VERSION 5.8 ;
BUSBITCHARS "[]" ;
DIVIDERCHAR "/" ;
UNITS
    DATABASE MICRONS 1000 ;
END UNITS

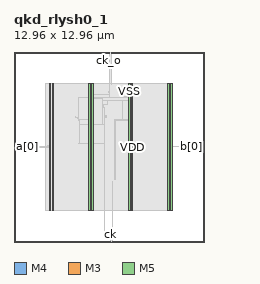
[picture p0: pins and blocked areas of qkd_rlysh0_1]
MACRO qkd_rlysh0_1
  FOREIGN qkd_rlysh0_1 0 0 ;
  CLASS BLOCK ;
  SIZE 12.96 BY 12.96 ;
  PIN a[0]
    DIRECTION INPUT ;
    USE SIGNAL ;
    PORT
      LAYER M4 ;
        RECT  0 6.48 0.084 6.504 ;
    END
  END a[0]
  PIN b[0]
    DIRECTION OUTPUT ;
    USE SIGNAL ;
    PORT
      LAYER M4 ;
        RECT  12.876 6.48 12.96 6.504 ;
    END
  END b[0]
  PIN ck
    DIRECTION INPUT ;
    USE SIGNAL ;
    PORT
      LAYER M3 ;
        RECT  6.588 0 6.606 0.037 ;
    END
  END ck
  PIN ck_o
    DIRECTION OUTPUT ;
    USE SIGNAL ;
    PORT
      LAYER M5 ;
        RECT  6.48 12.876 6.504 12.96 ;
    END
  END ck_o
  PIN eb
    DIRECTION OUTPUT ;
    USE SIGNAL ;
    PORT
      LAYER M5 ;
        RECT  6.624 12.876 6.648 12.96 ;
    END
  END eb
  PIN en
    DIRECTION INPUT ;
    USE SIGNAL ;
    PORT
      LAYER M3 ;
        RECT  6.696 0 6.714 0.037 ;
    END
  END en
  PIN VDD
    DIRECTION INOUT ;
    USE POWER ;
    PORT
      LAYER M5 ;
        RECT  10.692 2.151 10.812 10.809 ;
        RECT  7.992 2.151 8.112 10.809 ;
        RECT  5.292 2.151 5.412 10.809 ;
        RECT  2.592 2.151 2.712 10.809 ;
    END
  END VDD
  PIN VSS
    DIRECTION INOUT ;
    USE GROUND ;
    PORT
      LAYER M5 ;
        RECT  10.5 2.137 10.62 10.823 ;
        RECT  7.8 2.137 7.92 10.823 ;
        RECT  5.1 2.137 5.22 10.823 ;
        RECT  2.4 2.137 2.52 10.823 ;
    END
  END VSS
  OBS
    LAYER RVTN ;
     RECT  2.16 2.16 10.8 2.295 ;
     RECT  2.16 2.565 10.8 2.835 ;
     RECT  2.16 3.105 10.8 3.375 ;
     RECT  2.16 3.645 10.8 3.915 ;
     RECT  2.16 4.185 10.8 4.455 ;
     RECT  2.16 4.725 10.8 4.995 ;
     RECT  2.16 5.265 10.8 5.535 ;
     RECT  2.16 5.805 10.8 6.075 ;
     RECT  2.16 6.345 10.8 6.615 ;
     RECT  2.16 6.885 10.8 7.155 ;
     RECT  2.16 7.425 10.8 7.695 ;
     RECT  2.16 7.965 10.8 8.235 ;
     RECT  2.16 8.505 10.8 8.775 ;
     RECT  2.16 9.045 10.8 9.315 ;
     RECT  2.16 9.585 10.8 9.855 ;
     RECT  2.16 10.125 10.8 10.395 ;
     RECT  2.16 10.665 10.8 10.8 ;
    LAYER RVTP ;
     RECT  2.16 2.295 10.8 2.565 ;
     RECT  2.16 2.835 10.8 3.105 ;
     RECT  2.16 3.375 10.8 3.645 ;
     RECT  2.16 3.915 10.8 4.185 ;
     RECT  2.16 4.455 10.8 4.725 ;
     RECT  2.16 4.995 10.8 5.265 ;
     RECT  2.16 5.535 10.8 5.805 ;
     RECT  2.16 6.075 10.8 6.345 ;
     RECT  2.16 6.615 10.8 6.885 ;
     RECT  2.16 7.155 10.8 7.425 ;
     RECT  2.16 7.695 10.8 7.965 ;
     RECT  2.16 8.235 10.8 8.505 ;
     RECT  2.16 8.775 10.8 9.045 ;
     RECT  2.16 9.315 10.8 9.585 ;
     RECT  2.16 9.855 10.8 10.125 ;
     RECT  2.16 10.395 10.8 10.665 ;
    LAYER M1 ;
     RECT  2.16 2.151 10.8 10.809 ;
    LAYER M2 ;
     RECT  2.16 2.151 10.8 10.809 ;
     RECT  10.8 2.421 10.812 10.539 ;
     RECT  10.812 6.516 12.875 6.534 ;
    LAYER M3 ;
     RECT  6.588 0.012 6.714 0.557 ;
     RECT  2.415 2.143 2.505 2.413 ;
     RECT  5.115 2.143 5.205 2.413 ;
     RECT  7.815 2.143 7.905 2.413 ;
     RECT  10.515 2.143 10.605 2.413 ;
     RECT  6.696 0.557 6.714 4.145 ;
     RECT  5.115 2.413 5.397 5.881 ;
     RECT  2.415 2.413 2.697 6.475 ;
     RECT  12.852 6.475 12.87 6.539 ;
     RECT  2.304 6.475 2.697 6.575 ;
     RECT  5.115 5.881 6.102 6.691 ;
     RECT  4.428 6.691 6.102 6.749 ;
     RECT  5.115 6.749 6.102 7.963 ;
     RECT  5.115 7.963 6.138 8.299 ;
     RECT  6.876 4.261 6.894 8.311 ;
     RECT  7.815 2.413 8.097 8.311 ;
     RECT  6.876 8.311 8.097 8.339 ;
     RECT  4.392 8.299 6.138 8.435 ;
     RECT  5.115 8.435 6.138 8.509 ;
     RECT  4.176 8.491 4.194 8.537 ;
     RECT  5.115 8.509 6.282 8.621 ;
     RECT  5.115 8.621 6.138 9.391 ;
     RECT  5.115 9.391 6.354 9.625 ;
     RECT  7.416 8.339 8.097 9.625 ;
     RECT  5.115 9.625 8.097 9.851 ;
     RECT  7.38 9.851 8.097 9.923 ;
     RECT  5.115 9.851 6.498 10.049 ;
     RECT  6.48 10.049 6.498 10.253 ;
     RECT  2.415 6.575 2.697 10.547 ;
     RECT  5.115 10.049 5.397 10.547 ;
     RECT  7.815 9.923 8.097 10.547 ;
     RECT  10.515 2.413 10.797 10.547 ;
     RECT  7.815 10.547 7.974 10.661 ;
     RECT  2.415 10.547 2.505 10.817 ;
     RECT  5.115 10.547 5.205 10.817 ;
     RECT  7.815 10.661 7.905 10.817 ;
     RECT  10.515 10.547 10.605 10.817 ;
     RECT  6.66 10.741 6.678 10.829 ;
    LAYER M4 ;
     RECT  0.06 6.48 2.408 6.504 ;
     RECT  2.408 2.148 2.512 10.812 ;
     RECT  2.512 2.418 2.704 10.542 ;
     RECT  4.165 8.496 4.364 8.52 ;
     RECT  4.364 8.4 4.381 8.52 ;
     RECT  4.412 6.72 5.108 6.744 ;
     RECT  4.381 8.304 5.108 8.52 ;
     RECT  4.405 9.792 5.108 9.816 ;
     RECT  5.108 2.148 5.212 10.812 ;
     RECT  5.212 2.418 5.404 10.542 ;
     RECT  5.404 7.968 6.041 9.816 ;
     RECT  6.041 7.968 6.149 9.144 ;
     RECT  6.149 7.968 6.193 8.616 ;
     RECT  6.193 8.592 6.293 8.616 ;
     RECT  6.428 10.224 6.515 10.248 ;
     RECT  6.133 0.528 6.617 0.552 ;
     RECT  6.605 10.8 6.689 10.824 ;
     RECT  7.808 2.148 7.912 10.812 ;
     RECT  7.912 2.418 8.104 10.542 ;
     RECT  10.508 2.148 10.612 10.812 ;
     RECT  10.612 2.418 10.804 10.542 ;
     RECT  12.841 6.48 12.924 6.504 ;
    LAYER M5 ;
     RECT  6.144 0.517 6.168 2.137 ;
     RECT  2.4 2.137 2.52 2.151 ;
     RECT  7.8 2.137 7.92 2.151 ;
     RECT  10.5 2.137 10.62 2.151 ;
     RECT  5.1 2.137 6.168 6.709 ;
     RECT  4.464 6.709 6.168 8.003 ;
     RECT  4.464 8.003 5.412 8.389 ;
     RECT  4.416 8.389 5.412 9.827 ;
     RECT  6.48 10.213 6.504 10.789 ;
     RECT  2.4 2.151 2.712 10.809 ;
     RECT  5.1 9.827 5.412 10.809 ;
     RECT  7.8 2.151 8.112 10.809 ;
     RECT  10.5 2.151 10.812 10.809 ;
     RECT  2.4 10.809 2.52 10.823 ;
     RECT  5.1 10.809 5.22 10.823 ;
     RECT  7.8 10.809 7.92 10.823 ;
     RECT  10.5 10.809 10.62 10.823 ;
     RECT  6.48 10.789 6.648 12.944 ;
  END
END qkd_rlysh0_1
END LIBRARY
